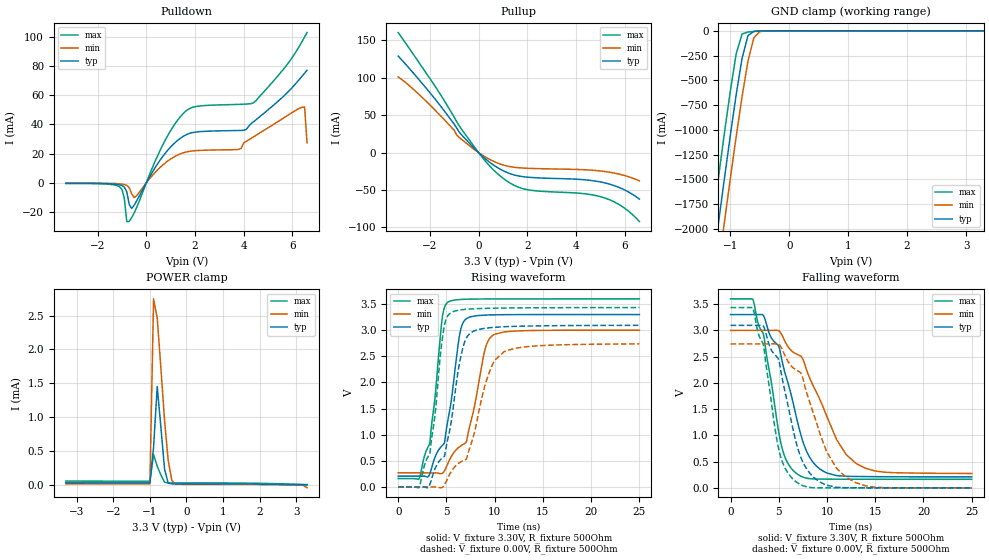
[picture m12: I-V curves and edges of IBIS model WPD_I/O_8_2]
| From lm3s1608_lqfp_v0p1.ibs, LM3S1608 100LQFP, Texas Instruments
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[Model]   WPD_I/O_8_2
Model_type   I/O
Vinl = 1.26
Vinh = 2.04
Vmeas = 1.65
| variable   typ   min   max
C_comp   9.739pF   9.739pF   9.739pF
[Model Spec]
Vinh+   1.91   1.78   2.04
Vinh-   1.90   1.76   2.03
Vinl+   1.40   1.27   1.54
Vinl-   1.39   1.26   1.53
| variable   typ   min   max
[Temperature Range]  25   85   -40
[Voltage Range]   3.3V   3.0V   3.6V
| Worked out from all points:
|   slope of the pulldown table from 0 to 0.495 V, typ, clamps not added: 35.8 ohm
|   slope of the pullup table from 0 to 0.495 V, typ, clamps not added: 35.8 ohm
|   GND clamp passes 1 mA (typ) near -0.48 V on its own axis
|   POWER clamp passes 1 mA (typ) near -0.72 V on its own axis
|   falling waveform, V_fixture 3.30V, R_fixture 500Ohm: 20-80 % time 2.58ns typ, 3.86ns min, 1.8ns max; typ from 3.3 V to 0.208 V
|   rising waveform, V_fixture 3.30V, R_fixture 500Ohm: 20-80 % time 1.45ns typ, 2.05ns min, 1.11ns max; typ from 0.208 V to 3.3 V
|   falling waveform, V_fixture 0.00V, R_fixture 500Ohm: 20-80 % time 2.32ns typ, 3.18ns min, 1.7ns max; typ from 3.09 V to 0 V
|   rising waveform, V_fixture 0.00V, R_fixture 500Ohm: 20-80 % time 1.64ns typ, 2.34ns min, 1.19ns max; typ from 0 V to 3.09 V
[Pulldown]
|  Voltage   I(typ)   I(min)   I(max)
-3.3V     -256.5uA   -145.6uA   -364.4uA
-1.1V     -1.273mA   -587.4uA   -2.566mA
-900mV    -2.885mA   -1.061mA   -10.54mA
-800mV    -5.992mA   -1.67mA    -26.39mA
-700mV    -14.71mA   -3.214mA   -26.32mA
-500mV    -15.25mA   -9.999mA   -20.65mA
600mV     16.35mA    11.13mA    23.4mA
1.5V      31.67mA    20.51mA    47.18mA
3.8V      35.87mA    22.99mA    53.71mA
4.4V      41.79mA    31.47mA    54.86mA
6.5V      75.05mA    51.94mA    99.75mA
6.6V      77.06mA    27.41mA    102.8mA
[Pullup]
|  Voltage   I(typ)   I(min)   I(max)
-3.3V     128.9mA    101.3mA    160.4mA
-2V       80.11mA    63.76mA    99.01mA
-1V       37.89mA    29.82mA    47.29mA
-700mV    23.8mA     17.69mA    31.26mA
300mV     -8.861mA   -6.312mA   -12.18mA
1V        -24.01mA   -16.38mA   -34.13mA
1.5V      -30.15mA   -19.7mA    -44.24mA
2V        -32.74mA   -20.87mA   -49.48mA
4.3V      -36.12mA   -22.8mA    -54.74mA
5.1V      -39.81mA   -24.88mA   -59.77mA
5.9V      -48.4mA    -29.75mA   -72.06mA
6.6V      -62.06mA   -37.61mA   -92.08mA
[GND Clamp]
|  Voltage   I(typ)   I(min)   I(max)
-3.3V     -11.72A    -12.12A    -11.3A
-1.4V     -2.845A    -3.285A    -2.387A
-1.3V     -2.39A     -2.831A    -1.93A
-1.2V     -1.938A    -2.38A     -1.478A
-1.1V     -1.494A    -1.934A    -1.036A
-1V       -1.059A    -1.496A    -610.6mA
-900mV    -645mA     -1.069A    -232.9mA
-800mV    -277.1mA   -664.4mA   -31.59mA
-700mV    -48.56mA   -306.6mA   -12.1mA
-600mV    -5.561mA   -70.2mA    -6.281mA
-500mV    -1.172mA   -7.88mA    -2.176mA
3.3V      16.11uA    11.84uA    29.77uA
[POWER Clamp]
|  Voltage   I(typ)   I(min)   I(max)
-3.3V     31.42uA    17.14uA    57.54uA
-1V       30.25uA    16.5uA     55.43uA
-900mV    557.3uA    2.746mA    449.1uA
-800mV    1.452mA    2.463mA    276.5uA
-700mV    854.2uA    1.726mA    147.8uA
-600mV    235.9uA    958.2uA    41.01uA
-500mV    28.31uA    363.4uA    30.71uA
-400mV    16.41uA    67.09uA    29.83uA
-300mV    16.12uA    11.84uA    29.79uA
3.1V      2.408uA    -920.8nA   9.197uA
3.2V      1.227uA    -3.925uA   7.474uA
3.3V      -104.7pA   -42.65uA   5.692uA
[Ramp]
| variable   typ   min   max
dV/dt_f   1.85/2.58n   1.63/3.86n   2.06/1.80n
dV/dt_r   1.86/1.64n   1.64/2.34n   2.06/1.19n
R_load = 500Ohm
[Falling Waveform]
V_fixture = 3.30V
V_fixture_min = 3.00V
V_fixture_max = 3.60V
R_fixture = 500Ohm
|   Time   V(typ)   V(min)   V(max)
0s        3.298V     2.996V     3.597V
2.3ns     3.298V     2.998V     3.592V
3.5ns     3.248V     2.999V     2.839V
5.3ns     2.452V     2.918V     786.5mV
6.8ns     1.367V     2.551V     279.2mV
7.8ns     732mV      2.289V     188.6mV
8.9ns     417mV      1.822V     168mV
11ns      232.3mV    917.2mV    164.8mV
13ns      216.9mV    466.5mV    163.7mV
25ns      208.1mV    273.3mV    162.3mV
[Rising Waveform]
V_fixture = 3.30V
V_fixture_min = 3.00V
V_fixture_max = 3.60V
R_fixture = 500Ohm
|   Time   V(typ)   V(min)   V(max)
0s        207.6mV    270.9mV    162.2mV
2.1ns     207.5mV    270.3mV    145.2mV
3.2ns     218.9mV    270mV      798.8mV
4.6ns     801mV      264.2mV    3.278V
5.1ns     1.225V     427.7mV    3.528V
6.7ns     3.133V     812.1mV    3.589V
7.1ns     3.222V     885.6mV    3.592V
9ns       3.287V     2.631V     3.596V
9.8ns     3.293V     2.9V       3.597V
25ns      3.299V     2.999V     3.598V
[Falling Waveform]
V_fixture = 0.00V
V_fixture_min = 0.00V
V_fixture_max = 0.00V
R_fixture = 500Ohm
|   Time   V(typ)   V(min)   V(max)
0s        3.093V     2.74V      3.433V
2.3ns     3.093V     2.74V      3.428V
3.4ns     3.081V     2.741V     2.726V
5.1ns     2.349V     2.717V     655.3mV
6.8ns     865.4mV    2.246V     114.4mV
7.4ns     530.8mV    2.143V     50.23mV
8.6ns     205mV      1.413V     3.197mV
10ns      49.96mV    679.7mV    1.012mV
12ns      1.944mV    197.7mV    79.11uV
25ns      34.69uV    47.25uV    16.6uV
[Rising Waveform]
V_fixture = 0.00V
V_fixture_min = 0.00V
V_fixture_max = 0.00V
R_fixture = 500Ohm
|   Time   V(typ)   V(min)   V(max)
0s        194.1uV    2.639mV    104.4uV
2.1ns     126.6uV    547.5uV    -16.33mV
3.3ns     58.04mV    274.2uV    658.3mV
4.6ns     559.9mV    -3.812mV   2.871V
5.4ns     1.141V     264.7mV    3.325V
6.3ns     2.316V     457.6mV    3.382V
7.1ns     2.86V      548.1mV    3.4V
9.3ns     3.043V     2.12V      3.417V
11ns      3.066V     2.592V     3.423V
25ns      3.092V     2.737V     3.432V
